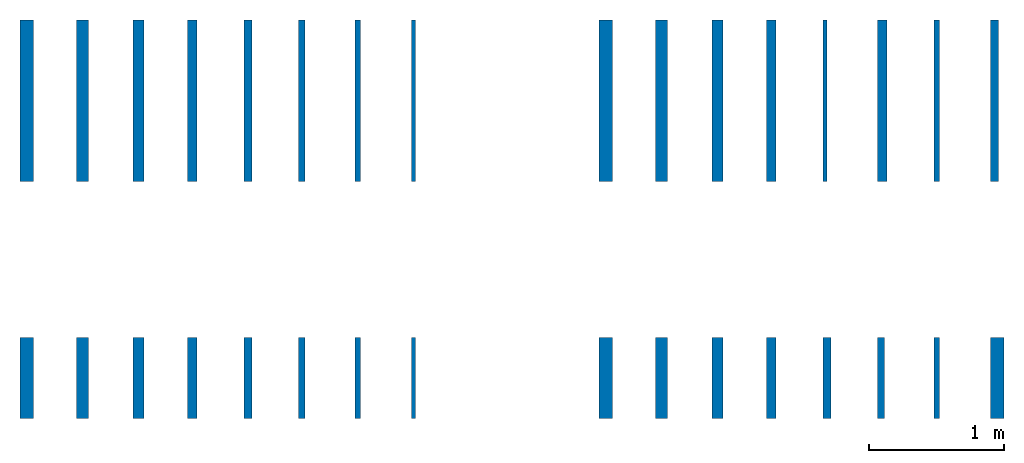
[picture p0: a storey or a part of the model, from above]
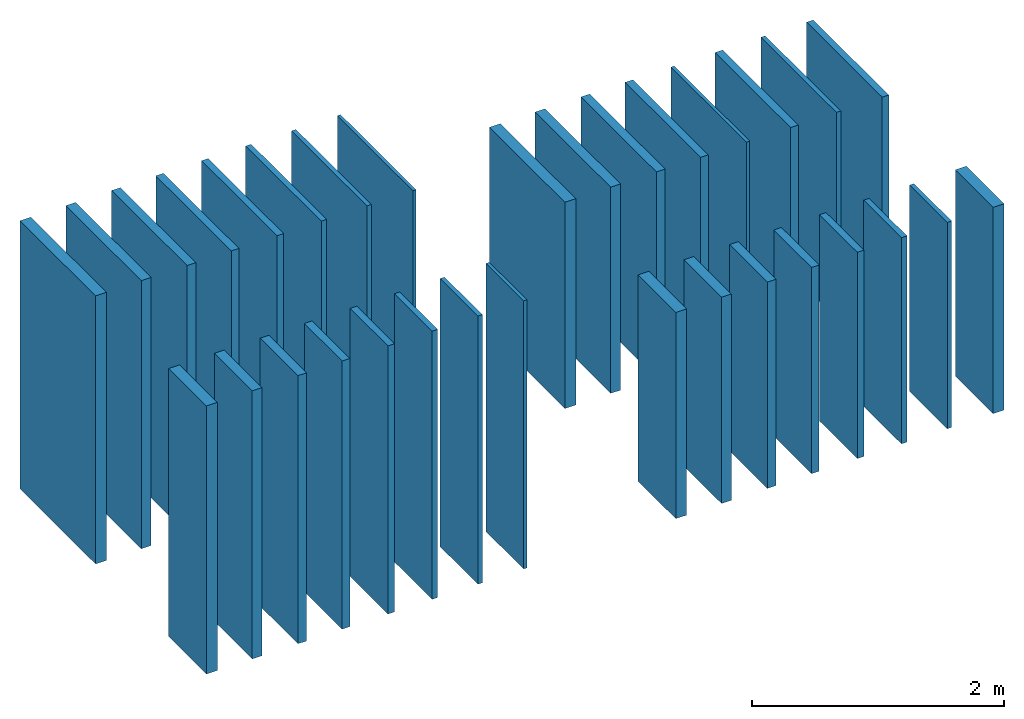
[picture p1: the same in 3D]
Properties of the parts of a building model (IFC2X3)

# File
Description: ViewDefinition [CoordinationView_V2.0]
File name: 0001
Time: 2017-06-22T09:40:16
Written by: The EXPRESS Data Manager Version 5.02.0100.07 : 28 Aug 2013
Made in: 20170223_1515(x64) - Exporter 18.0.0.420 - Alternate UI 18.0.0.420
Comment: STEP Physical File produced by: The EXPRESS Data Manager Version 5.02.0100.07 : 28 Aug 2013 * Module: EDMstepFileFactory/EDMstandAlone * Creation date: Thu Jun 22 09:40:16 2017 * Host: JAVIER * Database: C:\Users\JAVIER~1.DOM\AppData\Local\Temp\{031AC880-3D2B-48C9-9A60-2D267975EF29}\ifc * Database version: 5507 * Database creation date: Thu Jun 22 09:40:15 2017 * Schema: IFC2X3 * Model: DataRepository.ifc * Model creation date: Thu Jun 22 09:40:15 2017 * Header model: DataRepository.ifc_HeaderModel * Header model creation date: Thu Jun 22 09:40:15 2017 * EDMuser: sdai-user * EDMgroup: sdai-group * License ID and type: 5605 : Permanent license. Expiry date: * EDMstepFileFactory options: 020000

# IfcProject, 0001
LongName: Nombre de proyecto; Phase: Estado de proyecto

# IfcSite, Default
RefLatitude: 40, 24, 0, 5493; RefLongitude: -3, -40, -59, -880065; RefElevation: 0 m

# IfcBuilding
Pset_BuildingCommon - NumberOfStoreys: 1

# IfcBuildingStorey, Nivel 1
LongName: Nivel 1; Elevation: 0 m

# IfcWallStandardCase: Muro básico:Grafipol TR-30_2000x1200x40mm, Muro básico:Grafipol TR-30_2000x1200x40mm:170654
In: Nivel 1
Type - PredefinedType: STANDARD; Material: VALERO Grafipol® TR-30 0.04 m
Pset_WallCommon - LoadBearing: no; ExtendToStructure: no; IsExternal: no; Reference: Grafipol TR-30_2000x1200x40mm; FireRating: E; ThermalTransmittance: 0.75 kg/K/s3
Pset_ManufacturerTypeInformation - Manufacturer: Grupo Valero - José Manuel Valero, S. L.

# IfcWallStandardCase: Muro básico:Grafipol TR-30_2000x1200x70mm, Muro básico:Grafipol TR-30_2000x1200x70mm:170651
In: Nivel 1
Type - PredefinedType: STANDARD; Material: VALERO Grafipol® TR-30 0.07 m
Pset_WallCommon - LoadBearing: no; ExtendToStructure: no; IsExternal: no; Reference: Grafipol TR-30_2000x1200x70mm; FireRating: E; ThermalTransmittance: 0.428571 kg/K/s3
Pset_ManufacturerTypeInformation - Manufacturer: Grupo Valero - José Manuel Valero, S. L.

# IfcWallStandardCase: Muro básico:Grafipol TR-30_2000x1200x80mm, Muro básico:Grafipol TR-30_2000x1200x80mm:170650
In: Nivel 1
Type - PredefinedType: STANDARD; Material: VALERO Grafipol® TR-30 0.08 m
Pset_WallCommon - LoadBearing: no; ExtendToStructure: no; IsExternal: no; Reference: Grafipol TR-30_2000x1200x80mm; FireRating: E; ThermalTransmittance: 0.375 kg/K/s3
Pset_ManufacturerTypeInformation - Manufacturer: Grupo Valero - José Manuel Valero, S. L.

# IfcWallStandardCase: Muro básico:Grafipol TR-30_2000x1200x90mm, Muro básico:Grafipol TR-30_2000x1200x90mm:170649
In: Nivel 1
Type - PredefinedType: STANDARD; Material: VALERO Grafipol® TR-30 0.09 m
Pset_WallCommon - LoadBearing: no; ExtendToStructure: no; IsExternal: no; Reference: Grafipol TR-30_2000x1200x90mm; FireRating: E; ThermalTransmittance: 0.333333 kg/K/s3
Pset_ManufacturerTypeInformation - Manufacturer: Grupo Valero - José Manuel Valero, S. L.

# IfcWallStandardCase: Muro básico:Grafipol TR-30_2000x600x100mm, Muro básico:Grafipol TR-30_2000x600x100mm:166317
In: Nivel 1
Type - PredefinedType: STANDARD; Material: VALERO Grafipol® TR-30 0.1 m
Pset_WallCommon - Reference: Grafipol TR-30_2000x600x100mm; LoadBearing: no; ExtendToStructure: no; IsExternal: no; FireRating: E; ThermalTransmittance: 0.3 kg/K/s3
Pset_ManufacturerTypeInformation - Manufacturer: Grupo Valero - José Manuel Valero, S. L.

# IfcWallStandardCase: Muro básico:Grafipol TR-30_2000x600x40mm, Muro básico:Grafipol TR-30_2000x600x40mm:169338
In: Nivel 1
Type - PredefinedType: STANDARD; Material: VALERO Grafipol® TR-30 0.04 m
Pset_WallCommon - LoadBearing: no; ExtendToStructure: no; IsExternal: no; Reference: Grafipol TR-30_2000x600x40mm; FireRating: E; ThermalTransmittance: 0.75 kg/K/s3
Pset_ManufacturerTypeInformation - Manufacturer: Grupo Valero - José Manuel Valero, S. L.

# IfcWallStandardCase: Muro básico:Grafipol TR-30_2000x600x50mm, Muro básico:Grafipol TR-30_2000x600x50mm:169337
In: Nivel 1
Type - PredefinedType: STANDARD; Material: VALERO Grafipol® TR-30 0.05 m
Pset_WallCommon - LoadBearing: no; ExtendToStructure: no; IsExternal: no; Reference: Grafipol TR-30_2000x600x50mm; FireRating: E; ThermalTransmittance: 0.6 kg/K/s3
Pset_ManufacturerTypeInformation - Manufacturer: Grupo Valero - José Manuel Valero, S. L.

# IfcWallStandardCase: Muro básico:Grafipol TR-30_2000x600x60mm, Muro básico:Grafipol TR-30_2000x600x60mm:169316
In: Nivel 1
Type - PredefinedType: STANDARD; Material: VALERO Grafipol® TR-30 0.06 m
Pset_WallCommon - LoadBearing: no; ExtendToStructure: no; IsExternal: no; Reference: Grafipol TR-30_2000x600x60mm; FireRating: E; ThermalTransmittance: 0.5 kg/K/s3
Pset_ManufacturerTypeInformation - Manufacturer: Grupo Valero - José Manuel Valero, S. L.

# IfcWallStandardCase: Muro básico:Grafipol TR-30_2000x600x70mm, Muro básico:Grafipol TR-30_2000x600x70mm:169315
In: Nivel 1
Type - PredefinedType: STANDARD; Material: VALERO Grafipol® TR-30 0.07 m
Pset_WallCommon - LoadBearing: no; ExtendToStructure: no; IsExternal: no; Reference: Grafipol TR-30_2000x600x70mm; FireRating: E; ThermalTransmittance: 0.428571 kg/K/s3
Pset_ManufacturerTypeInformation - Manufacturer: Grupo Valero - José Manuel Valero, S. L.

# IfcWallStandardCase: Muro básico:Grafipol TR-30_2000x600x80mm, Muro básico:Grafipol TR-30_2000x600x80mm:169242
In: Nivel 1
Type - PredefinedType: STANDARD; Material: VALERO Grafipol® TR-30 0.08 m
Pset_WallCommon - LoadBearing: no; ExtendToStructure: no; IsExternal: no; Reference: Grafipol TR-30_2000x600x80mm; FireRating: E; ThermalTransmittance: 0.375 kg/K/s3
Pset_ManufacturerTypeInformation - Manufacturer: Grupo Valero - José Manuel Valero, S. L.

# IfcWallStandardCase: Muro básico:Grafipol TR-30_2000x600x90mm, Muro básico:Grafipol TR-30_2000x600x90mm:169207
In: Nivel 1
Type - PredefinedType: STANDARD; Material: VALERO Grafipol® TR-30 0.09 m
Pset_WallCommon - LoadBearing: no; ExtendToStructure: no; IsExternal: no; Reference: Grafipol TR-30_2000x600x90mm; FireRating: E; ThermalTransmittance: 0.333333 kg/K/s3
Pset_ManufacturerTypeInformation - Manufacturer: Grupo Valero - José Manuel Valero, S. L.

# IfcWallStandardCase: Muro básico:Grafipol TR-30_2600x1200x100mm (3)
In: Nivel 1
Type - PredefinedType: STANDARD; Material: VALERO Grafipol® TR-30 0.1 m
Pset_WallCommon - LoadBearing: no; ExtendToStructure: no; IsExternal: no; Reference: Grafipol TR-30_2600x1200x100mm; FireRating: E; ThermalTransmittance: 0.3 kg/K/s3
Pset_ManufacturerTypeInformation - Manufacturer: Grupo Valero - José Manuel Valero, S. L.
Name (Muro básico:Grafipol TR-30_2600x1200x100mm:...)
169380
170648
170656

# IfcWallStandardCase: Muro básico:Grafipol TR-30_2600x1200x30mm (2)
In: Nivel 1
Type - PredefinedType: STANDARD; Material: VALERO Grafipol® TR-30 0.03 m
Pset_WallCommon - LoadBearing: no; ExtendToStructure: no; IsExternal: no; ThermalTransmittance: 1 kg/K/s3; Reference: Grafipol TR-30_2600x1200x30mm; FireRating: E
Pset_ManufacturerTypeInformation - Manufacturer: Grupo Valero - José Manuel Valero, S. L.
Name (Muro básico:Grafipol TR-30_2600x1200x30mm:...)
170652
170663

# IfcWallStandardCase: Muro básico:Grafipol TR-30_2600x1200x40mm, Muro básico:Grafipol TR-30_2600x1200x40mm:170662
In: Nivel 1
Type - PredefinedType: STANDARD; Material: VALERO Grafipol® TR-30 0.04 m
Pset_WallCommon - LoadBearing: no; ExtendToStructure: no; IsExternal: no; Reference: Grafipol TR-30_2600x1200x40mm; FireRating: E; ThermalTransmittance: 0.75 kg/K/s3
Pset_ManufacturerTypeInformation - Manufacturer: Grupo Valero - José Manuel Valero, S. L.

# IfcWallStandardCase: Muro básico:Grafipol TR-30_2600x1200x50mm, Muro básico:Grafipol TR-30_2600x1200x50mm:170661
In: Nivel 1
Type - PredefinedType: STANDARD; Material: VALERO Grafipol® TR-30 0.05 m
Pset_WallCommon - LoadBearing: no; ExtendToStructure: no; IsExternal: no; Reference: Grafipol TR-30_2600x1200x50mm; FireRating: E; ThermalTransmittance: 0.6 kg/K/s3
Pset_ManufacturerTypeInformation - Manufacturer: Grupo Valero - José Manuel Valero, S. L.

# IfcWallStandardCase: Muro básico:Grafipol TR-30_2600x1200x60mm, Muro básico:Grafipol TR-30_2600x1200x60mm:170660
In: Nivel 1
Type - PredefinedType: STANDARD; Material: VALERO Grafipol® TR-30 0.06 m
Pset_WallCommon - LoadBearing: no; ExtendToStructure: no; IsExternal: no; ThermalTransmittance: 0.5 kg/K/s3; Reference: Grafipol TR-30_2600x1200x60mm; FireRating: E
Pset_ManufacturerTypeInformation - Manufacturer: Grupo Valero - José Manuel Valero, S. L.

# IfcWallStandardCase: Muro básico:Grafipol TR-30_2600x1200x70mm, Muro básico:Grafipol TR-30_2600x1200x70mm:170659
In: Nivel 1
Type - PredefinedType: STANDARD; Material: VALERO Grafipol® TR-30 0.07 m
Pset_WallCommon - LoadBearing: no; ExtendToStructure: no; IsExternal: no; Reference: Grafipol TR-30_2600x1200x70mm; FireRating: E; ThermalTransmittance: 0.428571 kg/K/s3
Pset_ManufacturerTypeInformation - Manufacturer: Grupo Valero - José Manuel Valero, S. L.

# IfcWallStandardCase: Muro básico:Grafipol TR-30_2600x1200x80mm, Muro básico:Grafipol TR-30_2600x1200x80mm:170658
In: Nivel 1
Type - PredefinedType: STANDARD; Material: VALERO Grafipol® TR-30 0.08 m
Pset_WallCommon - LoadBearing: no; ExtendToStructure: no; IsExternal: no; Reference: Grafipol TR-30_2600x1200x80mm; FireRating: E; ThermalTransmittance: 0.375 kg/K/s3
Pset_ManufacturerTypeInformation - Manufacturer: Grupo Valero - José Manuel Valero, S. L.

# IfcWallStandardCase: Muro básico:Grafipol TR-30_2600x1200x90mm, Muro básico:Grafipol TR-30_2600x1200x90mm:170657
In: Nivel 1
Type - PredefinedType: STANDARD; Material: VALERO Grafipol® TR-30 0.09 m
Pset_WallCommon - LoadBearing: no; ExtendToStructure: no; IsExternal: no; Reference: Grafipol TR-30_2600x1200x90mm; FireRating: E; ThermalTransmittance: 0.333333 kg/K/s3
Pset_ManufacturerTypeInformation - Manufacturer: Grupo Valero - José Manuel Valero, S. L.

# IfcWallStandardCase: Muro básico:Grafipol TR-30_2600x600x100mm, Muro básico:Grafipol TR-30_2600x600x100mm:169930
In: Nivel 1
Type - PredefinedType: STANDARD; Material: VALERO Grafipol® TR-30 0.1 m
Pset_WallCommon - LoadBearing: no; ExtendToStructure: no; IsExternal: no; Reference: Grafipol TR-30_2600x600x100mm; FireRating: E; ThermalTransmittance: 0.3 kg/K/s3
Pset_ManufacturerTypeInformation - Manufacturer: Grupo Valero - José Manuel Valero, S. L.

# IfcWallStandardCase: Muro básico:Grafipol TR-30_2600x600x30mm, Muro básico:Grafipol TR-30_2600x600x30mm:169937
In: Nivel 1
Type - PredefinedType: STANDARD; Material: VALERO Grafipol® TR-30 0.03 m
Pset_WallCommon - LoadBearing: no; ExtendToStructure: no; IsExternal: no; Reference: Grafipol TR-30_2600x600x30mm; FireRating: E; ThermalTransmittance: 1 kg/K/s3
Pset_ManufacturerTypeInformation - Manufacturer: Grupo Valero - José Manuel Valero, S. L.

# IfcWallStandardCase: Muro básico:Grafipol TR-30_2600x600x40mm, Muro básico:Grafipol TR-30_2600x600x40mm:169936
In: Nivel 1
Type - PredefinedType: STANDARD; Material: VALERO Grafipol® TR-30 0.04 m
Pset_WallCommon - LoadBearing: no; ExtendToStructure: no; IsExternal: no; Reference: Grafipol TR-30_2600x600x40mm; FireRating: E; ThermalTransmittance: 0.75 kg/K/s3
Pset_ManufacturerTypeInformation - Manufacturer: Grupo Valero - José Manuel Valero, S. L.

# IfcWallStandardCase: Muro básico:Grafipol TR-30_2600x600x50mm, Muro básico:Grafipol TR-30_2600x600x50mm:169935
In: Nivel 1
Type - PredefinedType: STANDARD; Material: VALERO Grafipol® TR-30 0.05 m
Pset_WallCommon - LoadBearing: no; ExtendToStructure: no; IsExternal: no; Reference: Grafipol TR-30_2600x600x50mm; FireRating: E; ThermalTransmittance: 0.6 kg/K/s3
Pset_ManufacturerTypeInformation - Manufacturer: Grupo Valero - José Manuel Valero, S. L.

# IfcWallStandardCase: Muro básico:Grafipol TR-30_2600x600x60mm (2)
In: Nivel 1
Type - PredefinedType: STANDARD; Material: VALERO Grafipol® TR-30 0.06 m
Pset_WallCommon - LoadBearing: no; ExtendToStructure: no; IsExternal: no; ThermalTransmittance: 0.5 kg/K/s3; Reference: Grafipol TR-30_2600x600x60mm; FireRating: E
Pset_ManufacturerTypeInformation - Manufacturer: Grupo Valero - José Manuel Valero, S. L.
Name (Muro básico:Grafipol TR-30_2600x600x60mm:...)
169934
170655

# IfcWallStandardCase: Muro básico:Grafipol TR-30_2600x600x70mm (2)
In: Nivel 1
Type - PredefinedType: STANDARD; Material: VALERO Grafipol® TR-30 0.07 m
Pset_WallCommon - LoadBearing: no; ExtendToStructure: no; IsExternal: no; Reference: Grafipol TR-30_2600x600x70mm; FireRating: E; ThermalTransmittance: 0.428571 kg/K/s3
Pset_ManufacturerTypeInformation - Manufacturer: Grupo Valero - José Manuel Valero, S. L.
Name (Muro básico:Grafipol TR-30_2600x600x70mm:...)
169933
170653

# IfcWallStandardCase: Muro básico:Grafipol TR-30_2600x600x80mm, Muro básico:Grafipol TR-30_2600x600x80mm:169932
In: Nivel 1
Type - PredefinedType: STANDARD; Material: VALERO Grafipol® TR-30 0.08 m
Pset_WallCommon - LoadBearing: no; ExtendToStructure: no; IsExternal: no; Reference: Grafipol TR-30_2600x600x80mm; FireRating: E; ThermalTransmittance: 0.375 kg/K/s3
Pset_ManufacturerTypeInformation - Manufacturer: Grupo Valero - José Manuel Valero, S. L.

# IfcWallStandardCase: Muro básico:Grafipol TR-30_2600x600x90mm, Muro básico:Grafipol TR-30_2600x600x90mm:169931
In: Nivel 1
Type - PredefinedType: STANDARD; Material: VALERO Grafipol® TR-30 0.09 m
Pset_WallCommon - LoadBearing: no; ExtendToStructure: no; IsExternal: no; Reference: Grafipol TR-30_2600x600x90mm; FireRating: E; ThermalTransmittance: 0.333333 kg/K/s3
Pset_ManufacturerTypeInformation - Manufacturer: Grupo Valero - José Manuel Valero, S. L.
